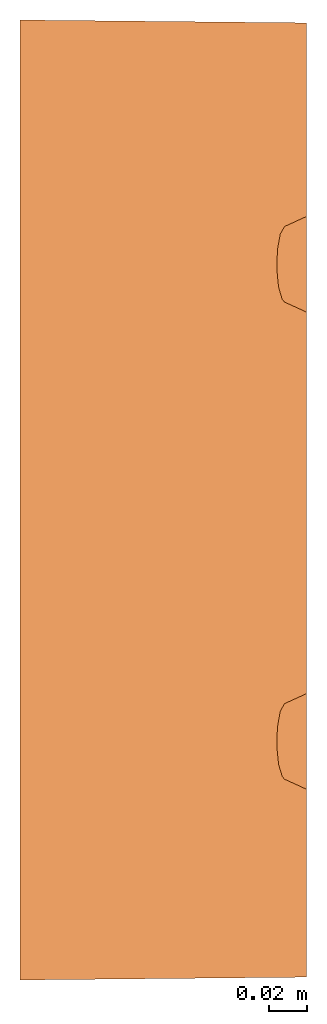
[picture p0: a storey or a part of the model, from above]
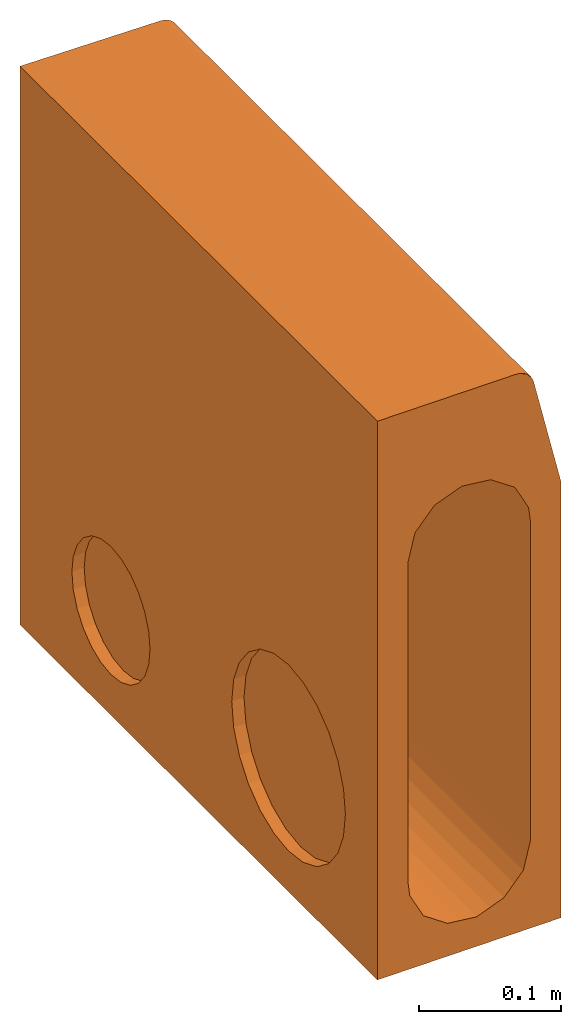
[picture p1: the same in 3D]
Properties of the parts of a building model (IFC2X3)

# File
Description: ViewDefinition [CoordinationView]
File name: 4937 - 25-11m internal mitre.ifc
Time: 2013-09-18T16:24:21
Written by: Autodesk Revit 2013
Made in: 20120221_2030(x64)

# IfcProject, Project Number
LongName: Project Name; Phase: Project Status

# IfcSite, Default
RefLatitude: 42, 21, 30, 344238; RefLongitude: -71, -3, -35, -194702; RefElevation: 0 mm

# IfcBuilding
Pset_BuildingCommon - NumberOfStoreys: 2
Other - Project Status: Project Status; Project Issue Date: Issue Date; Project Name: Project Name; Client Name: Owner; Project Address: Enter address here; Project Number: Project Number

# IfcBuildingStorey (2)
Graphics - Symbol: M_Level Head - Circle: M_Level Head - Circle; Symbol at End 1 Default: no; Symbol at End 2 Default: yes; Line Weight: 1; Color: 0; Line Pattern: Center
Constraints - Elevation Base: 0
Identity Data - Building Story: yes; Structural: no
Dimensions - Computation Height: 0 mm
Name | LongName = Name | Elevation (mm) = Constraints, Elevation (mm)
T.O. Fnd. Wall | T.O. Fnd. Wall | -300
Level 1 | Level 1 | 0

# IfcBuildingElementProxy: 4937 - 25-11m internal mitre, Civil-Drainage-Channel-ACO-KerbDrain-HB480(amar):4937 - 25-11m internal mitre:4937 - 25-11m internal mitre:481515
In: T.O. Fnd. Wall
Material: ACO Polymer Concrete.
Other - CreatedBy: www.aco.co.uk; Revision: 1
Green Building Properties - Access Cover/Frame Recycled Material Content: N/A; End Cap Recyclable: N/A; Access Cover/Frame Recyclable: N/A; Channel Recyclable: Fully recyclable; End Cap Recycled Material Content: N/A; Channel Recycled Material Content: 20% minimum
Data - Invert Depth: 455mm; Product Dimensions: 500/503mm x 150mm x 480mm (LxWxH); Concrete Surround Volume - Load Class A 15 - D 400 - Grass or Asphalt Pavement: N/A; Load Class: A 15 - D 400; Product Standard: BS EN 1433:2002, CE marked, Kitemarked; Drainage Slot Intake area: 14592mm²/m; ACO Hydraulic Design Software: http://www.acodesign.co.uk; Connection Pipe O.D: N/A; Drainage Slot Width: 50mm; Hydraulic Performance: http://www.aco.co.uk/download.php?id=120; Installation - Concrete Grade: Refer to brochure; Channel C.S.A: 0.04m²; Concrete Surround Volume - Load Class A 15 - D 400 - Concrete Pavement: N/A; Product Weight: 36.1 Kg
Constraints - Moves With Nearby Elements: no; Level: Level: Level 1
Dimensions - Volume: 16776158 mm3; Void Width: 150 mm; Void Start I/O: 0 mm; Mitre Long end: 495 mm; Mitre Small End: 498 mm; Mitre Void End: 355 mm; Mitre Void Start: 0 mm; Junction Start: 0 mm; Void End I/O: 150 mm; Void Length: 503 mm; junction void depth: 2000 mm; Straight Void Start: -4555 mm; Void Depth: -4561 mm; I/O endcap void depth: 2000 mm; Junction End: 150 mm
Phasing - Phase Created: Phase 1
Pset_BuildingElementProxyCommon - Reference: 4937 - 25-11m internal mitre
Construction - Centre Stone: no; HB480-500: no; perforated centre stone: no; RH drop kerb: no; 25-11m external mitre: no; LH inlet/outlet end cap: no; LH drop kerb: no; RH inlet/outlet end cap: no; Junction access unit: no; 10-8m external mitre: no; Closing end cap: no; 25-11m internal mitre: yes; KDHB480 500_blindunit: no; 7-6m external mitre: no; Junction end cap: no; RH BS transition kerb: no; Junction channel: no; LH BS transition kerb: no; Bus stop kerb: no; cable loop: no; Access Unit: no
Identity Data - Product Code: 4937; Cost: 0; Manufacturer: ACO Technologies plc - ACO Water Management Division; Model: ACO KerbDrain HB480; Fax: +44 (0)1462 815895; Product brochure: http://www.aco.co.uk/download.php?id=120; e-mail Sales: customersupport@aco.co.uk; Model Description: Combined kerb and drainage system; Product Page URL: http://www.aco.co.uk/product_detail.php?id=3; URL: www.aco.co.uk; Address: ACO Business Park, Hitchin Road, Shefford, Bedfordshire, United Kingdom SG17 5TE; Price: POA - contact ACO; Maintenance guidelines: http://www.aco.co.uk/download.php?id=120; Type Comments: ACO KerbDrain HB480 half battered 25-11m internal mitre unit 500/503mm long; Telephone: +44 (0)1462 816666; Installation guidelines: http://www.aco.co.uk/download.php?id=120; OmniClass Title: Rainwater Removal; e-mail Technical: technical@aco.co.uk; Assembly Code: D2040; OmniClass Number: 23.70.50.24; Assembly Description: Rain Water Drainage
General - SerialNumber: 0.000000; TagNumber: 0.000000
Materials and Finishes - End Cap Colour: N/A; Access Cover/Frame Colour: N/A; Connection Pipe Material: N/A; Channel Material: Vienite® Synthetic Resin Concrete; Access Cover/Frame Finish: N/A; Connection Pipe Material Colour: N/A; End Cap Material: N/A; Access Cover/Frame Material: N/A; Channel Colour: Grey

# IfcOpeningElement: Opening (3)
In: Level 1
Dimensions - Perimeter: 9790 mm; Area: 5901750 mm2; Volume: 2334261375 mm3; Thickness: 400 mm
Structural - Structural: no; Enable Analytical Model: no
Constraints - Height Offset From Level: 0 mm; Level: Level: Level 1; Room Bounding: yes; Related to Mass: no
Phasing - Phase Created: Phase 1
Graphics - Coarse Scale Fill Color: 0
Construction - Function: 0; Default Thickness: 400 mm
Analytical Properties - Roughness: 1; Absorptance: 0.1; Heat Transfer Coefficient (U): 2.0925; Thermal mass: 543920; Thermal Resistance (R): 0.477897
Materials and Finishes - Structural Material: Earth

# IfcSlab: Floor:Generic Floor - 400mm, Floor:Generic Floor - 400mm:136426
In: Level 1
PredefinedType: FLOOR; Material: Earth 400 mm
Dimensions - Perimeter: 9790 mm; Area: 5901750 mm2; Volume: 2334261375 mm3; Thickness: 400 mm
Structural - Structural: no; Enable Analytical Model: no
Constraints - Height Offset From Level: 0 mm; Level: Level: Level 1; Room Bounding: yes; Related to Mass: no
Phasing - Phase Created: Phase 1
Pset_SlabCommon - Reference: Generic Floor - 400mm; IsExternal: no; LoadBearing: yes
Graphics - Coarse Scale Fill Color: 0
Construction - Function: 0; Default Thickness: 400 mm
Analytical Properties - Roughness: 1; Absorptance: 0.1; Heat Transfer Coefficient (U): 2.0925; Thermal mass: 543920; Thermal Resistance (R): 0.477897
Materials and Finishes - Structural Material: Earth
